VERSION 5.7 ;
  NOWIREEXTENSIONATPIN ON ;
  DIVIDERCHAR "/" ;
  BUSBITCHARS "[]" ;
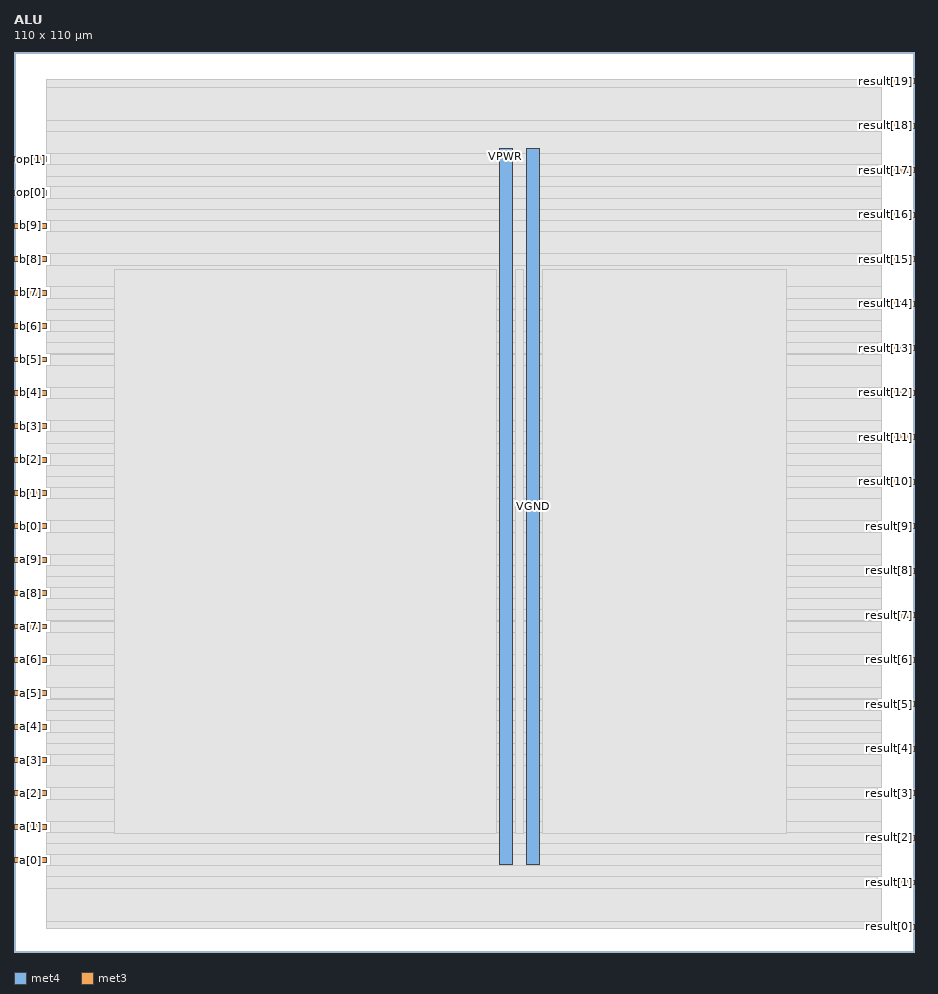
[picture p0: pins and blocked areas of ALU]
MACRO ALU
  CLASS BLOCK ;
  FOREIGN ALU ;
  ORIGIN 0.000 0.000 ;
  SIZE 110.000 BY 110.000 ;
  PIN VGND
    DIRECTION INOUT ;
    USE GROUND ;
    PORT
      LAYER met4 ;
        RECT 62.620 10.640 64.220 98.160 ;
    END
  END VGND
  PIN VPWR
    DIRECTION INOUT ;
    USE POWER ;
    PORT
      LAYER met4 ;
        RECT 59.320 10.640 60.920 98.160 ;
    END
  END VPWR
  PIN a[0]
    DIRECTION INPUT ;
    USE SIGNAL ;
    ANTENNAGATEAREA 0.631200 ;
    ANTENNADIFFAREA 0.434700 ;
    PORT
      LAYER met3 ;
        RECT 0.000 10.920 4.000 11.520 ;
    END
  END a[0]
  PIN a[1]
    DIRECTION INPUT ;
    USE SIGNAL ;
    ANTENNAGATEAREA 0.631200 ;
    ANTENNADIFFAREA 0.434700 ;
    PORT
      LAYER met3 ;
        RECT 0.000 15.000 4.000 15.600 ;
    END
  END a[1]
  PIN a[2]
    DIRECTION INPUT ;
    USE SIGNAL ;
    ANTENNAGATEAREA 0.631200 ;
    ANTENNADIFFAREA 0.434700 ;
    PORT
      LAYER met3 ;
        RECT 0.000 19.080 4.000 19.680 ;
    END
  END a[2]
  PIN a[3]
    DIRECTION INPUT ;
    USE SIGNAL ;
    ANTENNAGATEAREA 0.631200 ;
    ANTENNADIFFAREA 0.434700 ;
    PORT
      LAYER met3 ;
        RECT 0.000 23.160 4.000 23.760 ;
    END
  END a[3]
  PIN a[4]
    DIRECTION INPUT ;
    USE SIGNAL ;
    ANTENNAGATEAREA 0.631200 ;
    ANTENNADIFFAREA 0.434700 ;
    PORT
      LAYER met3 ;
        RECT 0.000 27.240 4.000 27.840 ;
    END
  END a[4]
  PIN a[5]
    DIRECTION INPUT ;
    USE SIGNAL ;
    ANTENNAGATEAREA 0.647700 ;
    ANTENNADIFFAREA 0.434700 ;
    PORT
      LAYER met3 ;
        RECT 0.000 31.320 4.000 31.920 ;
    END
  END a[5]
  PIN a[6]
    DIRECTION INPUT ;
    USE SIGNAL ;
    ANTENNAGATEAREA 0.647700 ;
    ANTENNADIFFAREA 0.434700 ;
    PORT
      LAYER met3 ;
        RECT 0.000 35.400 4.000 36.000 ;
    END
  END a[6]
  PIN a[7]
    DIRECTION INPUT ;
    USE SIGNAL ;
    ANTENNAGATEAREA 0.647700 ;
    ANTENNADIFFAREA 0.434700 ;
    PORT
      LAYER met3 ;
        RECT 0.000 39.480 4.000 40.080 ;
    END
  END a[7]
  PIN a[8]
    DIRECTION INPUT ;
    USE SIGNAL ;
    ANTENNAGATEAREA 0.631200 ;
    ANTENNADIFFAREA 0.434700 ;
    PORT
      LAYER met3 ;
        RECT 0.000 43.560 4.000 44.160 ;
    END
  END a[8]
  PIN a[9]
    DIRECTION INPUT ;
    USE SIGNAL ;
    ANTENNAGATEAREA 0.631200 ;
    ANTENNADIFFAREA 0.434700 ;
    PORT
      LAYER met3 ;
        RECT 0.000 47.640 4.000 48.240 ;
    END
  END a[9]
  PIN b[0]
    DIRECTION INPUT ;
    USE SIGNAL ;
    ANTENNAGATEAREA 0.647700 ;
    ANTENNADIFFAREA 0.434700 ;
    PORT
      LAYER met3 ;
        RECT 0.000 51.720 4.000 52.320 ;
    END
  END b[0]
  PIN b[1]
    DIRECTION INPUT ;
    USE SIGNAL ;
    ANTENNAGATEAREA 0.682200 ;
    ANTENNADIFFAREA 0.434700 ;
    PORT
      LAYER met3 ;
        RECT 0.000 55.800 4.000 56.400 ;
    END
  END b[1]
  PIN b[2]
    DIRECTION INPUT ;
    USE SIGNAL ;
    ANTENNAGATEAREA 0.631200 ;
    ANTENNADIFFAREA 0.434700 ;
    PORT
      LAYER met3 ;
        RECT 0.000 59.880 4.000 60.480 ;
    END
  END b[2]
  PIN b[3]
    DIRECTION INPUT ;
    USE SIGNAL ;
    ANTENNAGATEAREA 0.647700 ;
    ANTENNADIFFAREA 0.434700 ;
    PORT
      LAYER met3 ;
        RECT 0.000 63.960 4.000 64.560 ;
    END
  END b[3]
  PIN b[4]
    DIRECTION INPUT ;
    USE SIGNAL ;
    ANTENNAGATEAREA 0.631200 ;
    ANTENNADIFFAREA 0.434700 ;
    PORT
      LAYER met3 ;
        RECT 0.000 68.040 4.000 68.640 ;
    END
  END b[4]
  PIN b[5]
    DIRECTION INPUT ;
    USE SIGNAL ;
    ANTENNAGATEAREA 0.631200 ;
    ANTENNADIFFAREA 0.434700 ;
    PORT
      LAYER met3 ;
        RECT 0.000 72.120 4.000 72.720 ;
    END
  END b[5]
  PIN b[6]
    DIRECTION INPUT ;
    USE SIGNAL ;
    ANTENNAGATEAREA 0.631200 ;
    ANTENNADIFFAREA 0.434700 ;
    PORT
      LAYER met3 ;
        RECT 0.000 76.200 4.000 76.800 ;
    END
  END b[6]
  PIN b[7]
    DIRECTION INPUT ;
    USE SIGNAL ;
    ANTENNAGATEAREA 0.929700 ;
    ANTENNADIFFAREA 0.434700 ;
    PORT
      LAYER met3 ;
        RECT 0.000 80.280 4.000 80.880 ;
    END
  END b[7]
  PIN b[8]
    DIRECTION INPUT ;
    USE SIGNAL ;
    ANTENNAGATEAREA 0.631200 ;
    ANTENNADIFFAREA 0.434700 ;
    PORT
      LAYER met3 ;
        RECT 0.000 84.360 4.000 84.960 ;
    END
  END b[8]
  PIN b[9]
    DIRECTION INPUT ;
    USE SIGNAL ;
    ANTENNAGATEAREA 0.647700 ;
    ANTENNADIFFAREA 0.434700 ;
    PORT
      LAYER met3 ;
        RECT 0.000 88.440 4.000 89.040 ;
    END
  END b[9]
  PIN op[0]
    DIRECTION INPUT ;
    USE SIGNAL ;
    ANTENNAGATEAREA 0.593700 ;
    ANTENNADIFFAREA 0.434700 ;
    PORT
      LAYER met3 ;
        RECT 0.000 92.520 4.000 93.120 ;
    END
  END op[0]
  PIN op[1]
    DIRECTION INPUT ;
    USE SIGNAL ;
    ANTENNAGATEAREA 0.647700 ;
    ANTENNADIFFAREA 0.434700 ;
    PORT
      LAYER met3 ;
        RECT 0.000 96.600 4.000 97.200 ;
    END
  END op[1]
  PIN result[0]
    DIRECTION OUTPUT ;
    USE SIGNAL ;
    ANTENNADIFFAREA 0.445500 ;
    PORT
      LAYER met3 ;
        RECT 106.000 2.760 110.000 3.360 ;
    END
  END result[0]
  PIN result[10]
    DIRECTION OUTPUT ;
    USE SIGNAL ;
    ANTENNADIFFAREA 1.336500 ;
    PORT
      LAYER met3 ;
        RECT 106.000 57.160 110.000 57.760 ;
    END
  END result[10]
  PIN result[11]
    DIRECTION OUTPUT ;
    USE SIGNAL ;
    ANTENNADIFFAREA 0.891000 ;
    PORT
      LAYER met3 ;
        RECT 106.000 62.600 110.000 63.200 ;
    END
  END result[11]
  PIN result[12]
    DIRECTION OUTPUT ;
    USE SIGNAL ;
    ANTENNADIFFAREA 1.336500 ;
    PORT
      LAYER met3 ;
        RECT 106.000 68.040 110.000 68.640 ;
    END
  END result[12]
  PIN result[13]
    DIRECTION OUTPUT ;
    USE SIGNAL ;
    ANTENNADIFFAREA 0.795200 ;
    PORT
      LAYER met3 ;
        RECT 106.000 73.480 110.000 74.080 ;
    END
  END result[13]
  PIN result[14]
    DIRECTION OUTPUT ;
    USE SIGNAL ;
    ANTENNADIFFAREA 1.336500 ;
    PORT
      LAYER met3 ;
        RECT 106.000 78.920 110.000 79.520 ;
    END
  END result[14]
  PIN result[15]
    DIRECTION OUTPUT ;
    USE SIGNAL ;
    ANTENNADIFFAREA 1.336500 ;
    PORT
      LAYER met3 ;
        RECT 106.000 84.360 110.000 84.960 ;
    END
  END result[15]
  PIN result[16]
    DIRECTION OUTPUT ;
    USE SIGNAL ;
    ANTENNADIFFAREA 0.795200 ;
    PORT
      LAYER met3 ;
        RECT 106.000 89.800 110.000 90.400 ;
    END
  END result[16]
  PIN result[17]
    DIRECTION OUTPUT ;
    USE SIGNAL ;
    ANTENNADIFFAREA 0.340600 ;
    PORT
      LAYER met3 ;
        RECT 106.000 95.240 110.000 95.840 ;
    END
  END result[17]
  PIN result[18]
    DIRECTION OUTPUT ;
    USE SIGNAL ;
    ANTENNADIFFAREA 0.340600 ;
    PORT
      LAYER met3 ;
        RECT 106.000 100.680 110.000 101.280 ;
    END
  END result[18]
  PIN result[19]
    DIRECTION OUTPUT ;
    USE SIGNAL ;
    ANTENNADIFFAREA 0.340600 ;
    PORT
      LAYER met3 ;
        RECT 106.000 106.120 110.000 106.720 ;
    END
  END result[19]
  PIN result[1]
    DIRECTION OUTPUT ;
    USE SIGNAL ;
    ANTENNADIFFAREA 0.445500 ;
    PORT
      LAYER met3 ;
        RECT 106.000 8.200 110.000 8.800 ;
    END
  END result[1]
  PIN result[2]
    DIRECTION OUTPUT ;
    USE SIGNAL ;
    ANTENNADIFFAREA 0.445500 ;
    PORT
      LAYER met3 ;
        RECT 106.000 13.640 110.000 14.240 ;
    END
  END result[2]
  PIN result[3]
    DIRECTION OUTPUT ;
    USE SIGNAL ;
    ANTENNADIFFAREA 0.445500 ;
    PORT
      LAYER met3 ;
        RECT 106.000 19.080 110.000 19.680 ;
    END
  END result[3]
  PIN result[4]
    DIRECTION OUTPUT ;
    USE SIGNAL ;
    ANTENNADIFFAREA 0.445500 ;
    PORT
      LAYER met3 ;
        RECT 106.000 24.520 110.000 25.120 ;
    END
  END result[4]
  PIN result[5]
    DIRECTION OUTPUT ;
    USE SIGNAL ;
    ANTENNADIFFAREA 0.445500 ;
    PORT
      LAYER met3 ;
        RECT 106.000 29.960 110.000 30.560 ;
    END
  END result[5]
  PIN result[6]
    DIRECTION OUTPUT ;
    USE SIGNAL ;
    ANTENNADIFFAREA 0.445500 ;
    PORT
      LAYER met3 ;
        RECT 106.000 35.400 110.000 36.000 ;
    END
  END result[6]
  PIN result[7]
    DIRECTION OUTPUT ;
    USE SIGNAL ;
    ANTENNADIFFAREA 0.445500 ;
    PORT
      LAYER met3 ;
        RECT 106.000 40.840 110.000 41.440 ;
    END
  END result[7]
  PIN result[8]
    DIRECTION OUTPUT ;
    USE SIGNAL ;
    ANTENNADIFFAREA 1.336500 ;
    PORT
      LAYER met3 ;
        RECT 106.000 46.280 110.000 46.880 ;
    END
  END result[8]
  PIN result[9]
    DIRECTION OUTPUT ;
    USE SIGNAL ;
    ANTENNADIFFAREA 1.782000 ;
    PORT
      LAYER met3 ;
        RECT 106.000 51.720 110.000 52.320 ;
    END
  END result[9]
  OBS
      LAYER nwell ;
        RECT 9.930 10.795 100.010 98.005 ;
      LAYER li1 ;
        RECT 10.120 10.795 99.820 98.005 ;
      LAYER met1 ;
        RECT 5.130 9.560 100.120 99.920 ;
      LAYER met2 ;
        RECT 5.150 2.875 98.800 106.605 ;
      LAYER met3 ;
        RECT 4.000 105.720 105.600 106.585 ;
        RECT 4.000 101.680 106.000 105.720 ;
        RECT 4.000 100.280 105.600 101.680 ;
        RECT 4.000 97.600 106.000 100.280 ;
        RECT 4.400 96.240 106.000 97.600 ;
        RECT 4.400 96.200 105.600 96.240 ;
        RECT 4.000 94.840 105.600 96.200 ;
        RECT 4.000 93.520 106.000 94.840 ;
        RECT 4.400 92.120 106.000 93.520 ;
        RECT 4.000 90.800 106.000 92.120 ;
        RECT 4.000 89.440 105.600 90.800 ;
        RECT 4.400 89.400 105.600 89.440 ;
        RECT 4.400 88.040 106.000 89.400 ;
        RECT 4.000 85.360 106.000 88.040 ;
        RECT 4.400 83.960 105.600 85.360 ;
        RECT 4.000 81.280 106.000 83.960 ;
        RECT 4.400 79.920 106.000 81.280 ;
        RECT 4.400 79.880 105.600 79.920 ;
        RECT 4.000 78.520 105.600 79.880 ;
        RECT 4.000 77.200 106.000 78.520 ;
        RECT 4.400 75.800 106.000 77.200 ;
        RECT 4.000 74.480 106.000 75.800 ;
        RECT 4.000 73.120 105.600 74.480 ;
        RECT 4.400 73.080 105.600 73.120 ;
        RECT 4.400 71.720 106.000 73.080 ;
        RECT 4.000 69.040 106.000 71.720 ;
        RECT 4.400 67.640 105.600 69.040 ;
        RECT 4.000 64.960 106.000 67.640 ;
        RECT 4.400 63.600 106.000 64.960 ;
        RECT 4.400 63.560 105.600 63.600 ;
        RECT 4.000 62.200 105.600 63.560 ;
        RECT 4.000 60.880 106.000 62.200 ;
        RECT 4.400 59.480 106.000 60.880 ;
        RECT 4.000 58.160 106.000 59.480 ;
        RECT 4.000 56.800 105.600 58.160 ;
        RECT 4.400 56.760 105.600 56.800 ;
        RECT 4.400 55.400 106.000 56.760 ;
        RECT 4.000 52.720 106.000 55.400 ;
        RECT 4.400 51.320 105.600 52.720 ;
        RECT 4.000 48.640 106.000 51.320 ;
        RECT 4.400 47.280 106.000 48.640 ;
        RECT 4.400 47.240 105.600 47.280 ;
        RECT 4.000 45.880 105.600 47.240 ;
        RECT 4.000 44.560 106.000 45.880 ;
        RECT 4.400 43.160 106.000 44.560 ;
        RECT 4.000 41.840 106.000 43.160 ;
        RECT 4.000 40.480 105.600 41.840 ;
        RECT 4.400 40.440 105.600 40.480 ;
        RECT 4.400 39.080 106.000 40.440 ;
        RECT 4.000 36.400 106.000 39.080 ;
        RECT 4.400 35.000 105.600 36.400 ;
        RECT 4.000 32.320 106.000 35.000 ;
        RECT 4.400 30.960 106.000 32.320 ;
        RECT 4.400 30.920 105.600 30.960 ;
        RECT 4.000 29.560 105.600 30.920 ;
        RECT 4.000 28.240 106.000 29.560 ;
        RECT 4.400 26.840 106.000 28.240 ;
        RECT 4.000 25.520 106.000 26.840 ;
        RECT 4.000 24.160 105.600 25.520 ;
        RECT 4.400 24.120 105.600 24.160 ;
        RECT 4.400 22.760 106.000 24.120 ;
        RECT 4.000 20.080 106.000 22.760 ;
        RECT 4.400 18.680 105.600 20.080 ;
        RECT 4.000 16.000 106.000 18.680 ;
        RECT 4.400 14.640 106.000 16.000 ;
        RECT 4.400 14.600 105.600 14.640 ;
        RECT 4.000 13.240 105.600 14.600 ;
        RECT 4.000 11.920 106.000 13.240 ;
        RECT 4.400 10.520 106.000 11.920 ;
        RECT 4.000 9.200 106.000 10.520 ;
        RECT 4.000 7.800 105.600 9.200 ;
        RECT 4.000 3.760 106.000 7.800 ;
        RECT 4.000 2.895 105.600 3.760 ;
      LAYER met4 ;
        RECT 12.255 14.455 58.920 83.465 ;
        RECT 61.320 14.455 62.220 83.465 ;
        RECT 64.620 14.455 94.465 83.465 ;
  END
END ALU
END LIBRARY

